###############################################################
#  Generated by:      Cadence Innovus 21.18-s099_1
#  OS:                Linux x86_64(Host ID ncdc-0137)
#  Generated on:      Wed Aug 12 09:11:18 2026
#  Design:            riscv_core
#  Command:           write_lef_abstract /home/cc/Documents/Abdullah/RISCV_synthesis/export/Innovus_Data/outputs/pnr/riscv_core_macro.lef -stripe_pins
###############################################################

VERSION 5.8 ;

BUSBITCHARS "[]" ;
DIVIDERCHAR "/" ;

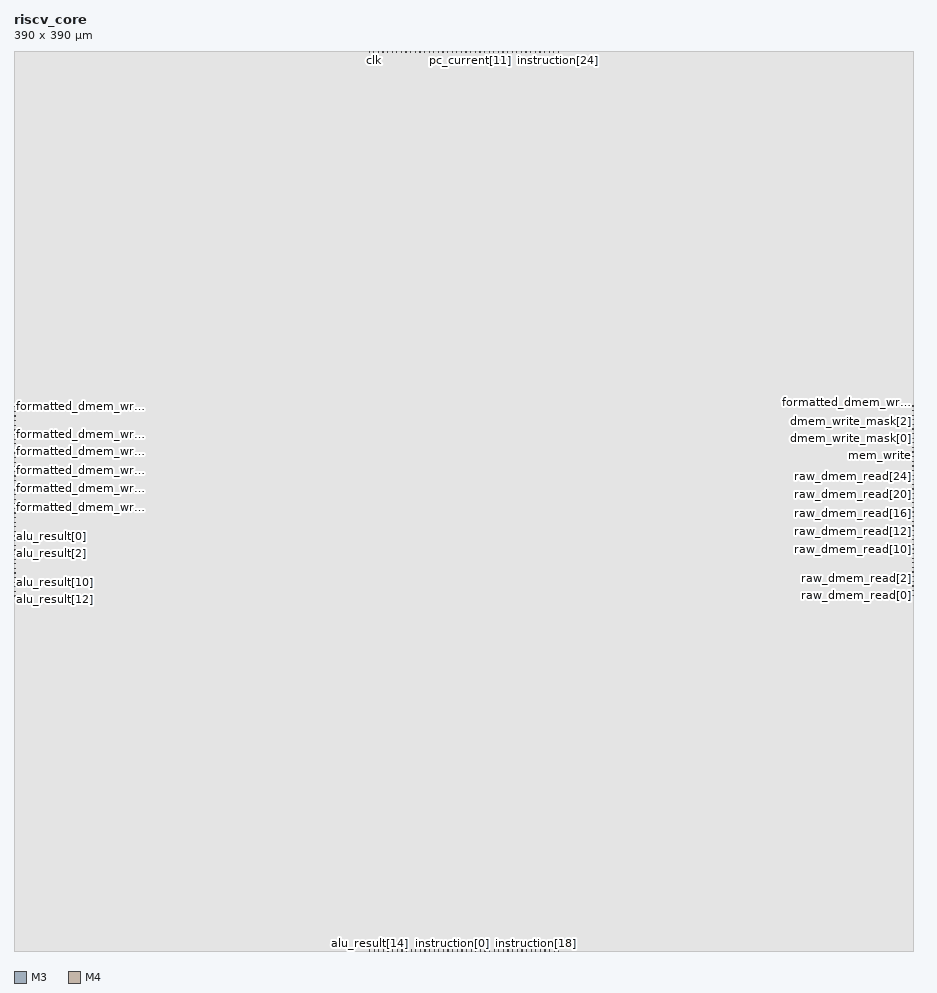
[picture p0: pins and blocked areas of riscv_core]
MACRO riscv_core
  CLASS BLOCK ;
  SIZE 390.000000 BY 390.000000 ;
  FOREIGN riscv_core -195.000000 -195.000000 ;
  ORIGIN 0 0 ;
  SYMMETRY X Y R90 ;
  PIN rst
    DIRECTION INPUT ;
    USE SIGNAL ;
    PORT
      LAYER M3 ;
        RECT 153.850000 389.480000 153.950000 390.000000 ;
    END
  END rst
  PIN clk
    DIRECTION INPUT ;
    USE SIGNAL ;
    PORT
      LAYER M3 ;
        RECT 155.850000 389.480000 155.950000 390.000000 ;
    END
  END clk
  PIN pc_current[31]
    DIRECTION OUTPUT ;
    USE SIGNAL ;
    PORT
      LAYER M3 ;
        RECT 157.850000 389.480000 157.950000 390.000000 ;
    END
  END pc_current[31]
  PIN pc_current[30]
    DIRECTION OUTPUT ;
    USE SIGNAL ;
    PORT
      LAYER M3 ;
        RECT 159.850000 389.480000 159.950000 390.000000 ;
    END
  END pc_current[30]
  PIN pc_current[29]
    DIRECTION OUTPUT ;
    USE SIGNAL ;
    PORT
      LAYER M3 ;
        RECT 161.850000 389.480000 161.950000 390.000000 ;
    END
  END pc_current[29]
  PIN pc_current[28]
    DIRECTION OUTPUT ;
    USE SIGNAL ;
    PORT
      LAYER M3 ;
        RECT 163.850000 389.480000 163.950000 390.000000 ;
    END
  END pc_current[28]
  PIN pc_current[27]
    DIRECTION OUTPUT ;
    USE SIGNAL ;
    PORT
      LAYER M3 ;
        RECT 165.850000 389.480000 165.950000 390.000000 ;
    END
  END pc_current[27]
  PIN pc_current[26]
    DIRECTION OUTPUT ;
    USE SIGNAL ;
    PORT
      LAYER M3 ;
        RECT 167.850000 389.480000 167.950000 390.000000 ;
    END
  END pc_current[26]
  PIN pc_current[25]
    DIRECTION OUTPUT ;
    USE SIGNAL ;
    PORT
      LAYER M3 ;
        RECT 169.850000 389.480000 169.950000 390.000000 ;
    END
  END pc_current[25]
  PIN pc_current[24]
    DIRECTION OUTPUT ;
    USE SIGNAL ;
    PORT
      LAYER M3 ;
        RECT 171.850000 389.480000 171.950000 390.000000 ;
    END
  END pc_current[24]
  PIN pc_current[23]
    DIRECTION OUTPUT ;
    USE SIGNAL ;
    PORT
      LAYER M3 ;
        RECT 173.850000 389.480000 173.950000 390.000000 ;
    END
  END pc_current[23]
  PIN pc_current[22]
    DIRECTION OUTPUT ;
    USE SIGNAL ;
    PORT
      LAYER M3 ;
        RECT 175.850000 389.480000 175.950000 390.000000 ;
    END
  END pc_current[22]
  PIN pc_current[21]
    DIRECTION OUTPUT ;
    USE SIGNAL ;
    PORT
      LAYER M3 ;
        RECT 177.850000 389.480000 177.950000 390.000000 ;
    END
  END pc_current[21]
  PIN pc_current[20]
    DIRECTION OUTPUT ;
    USE SIGNAL ;
    PORT
      LAYER M3 ;
        RECT 179.850000 389.480000 179.950000 390.000000 ;
    END
  END pc_current[20]
  PIN pc_current[19]
    DIRECTION OUTPUT ;
    USE SIGNAL ;
    PORT
      LAYER M3 ;
        RECT 181.850000 389.480000 181.950000 390.000000 ;
    END
  END pc_current[19]
  PIN pc_current[18]
    DIRECTION OUTPUT ;
    USE SIGNAL ;
    PORT
      LAYER M3 ;
        RECT 183.850000 389.480000 183.950000 390.000000 ;
    END
  END pc_current[18]
  PIN pc_current[17]
    DIRECTION OUTPUT ;
    USE SIGNAL ;
    PORT
      LAYER M3 ;
        RECT 185.850000 389.480000 185.950000 390.000000 ;
    END
  END pc_current[17]
  PIN pc_current[16]
    DIRECTION OUTPUT ;
    USE SIGNAL ;
    PORT
      LAYER M3 ;
        RECT 187.850000 389.480000 187.950000 390.000000 ;
    END
  END pc_current[16]
  PIN pc_current[15]
    DIRECTION OUTPUT ;
    USE SIGNAL ;
    PORT
      LAYER M3 ;
        RECT 189.850000 389.480000 189.950000 390.000000 ;
    END
  END pc_current[15]
  PIN pc_current[14]
    DIRECTION OUTPUT ;
    USE SIGNAL ;
    PORT
      LAYER M3 ;
        RECT 191.850000 389.480000 191.950000 390.000000 ;
    END
  END pc_current[14]
  PIN pc_current[13]
    DIRECTION OUTPUT ;
    USE SIGNAL ;
    PORT
      LAYER M3 ;
        RECT 193.850000 389.480000 193.950000 390.000000 ;
    END
  END pc_current[13]
  PIN pc_current[12]
    DIRECTION OUTPUT ;
    USE SIGNAL ;
    PORT
      LAYER M3 ;
        RECT 195.850000 389.480000 195.950000 390.000000 ;
    END
  END pc_current[12]
  PIN pc_current[11]
    DIRECTION OUTPUT ;
    USE SIGNAL ;
    PORT
      LAYER M3 ;
        RECT 197.850000 389.480000 197.950000 390.000000 ;
    END
  END pc_current[11]
  PIN pc_current[10]
    DIRECTION OUTPUT ;
    USE SIGNAL ;
    PORT
      LAYER M3 ;
        RECT 199.850000 389.480000 199.950000 390.000000 ;
    END
  END pc_current[10]
  PIN pc_current[9]
    DIRECTION OUTPUT ;
    USE SIGNAL ;
    PORT
      LAYER M3 ;
        RECT 201.850000 389.480000 201.950000 390.000000 ;
    END
  END pc_current[9]
  PIN pc_current[8]
    DIRECTION OUTPUT ;
    USE SIGNAL ;
    PORT
      LAYER M3 ;
        RECT 203.850000 389.480000 203.950000 390.000000 ;
    END
  END pc_current[8]
  PIN pc_current[7]
    DIRECTION OUTPUT ;
    USE SIGNAL ;
    PORT
      LAYER M3 ;
        RECT 205.850000 389.480000 205.950000 390.000000 ;
    END
  END pc_current[7]
  PIN pc_current[6]
    DIRECTION OUTPUT ;
    USE SIGNAL ;
    PORT
      LAYER M3 ;
        RECT 207.850000 389.480000 207.950000 390.000000 ;
    END
  END pc_current[6]
  PIN pc_current[5]
    DIRECTION OUTPUT ;
    USE SIGNAL ;
    PORT
      LAYER M3 ;
        RECT 209.850000 389.480000 209.950000 390.000000 ;
    END
  END pc_current[5]
  PIN pc_current[4]
    DIRECTION OUTPUT ;
    USE SIGNAL ;
    PORT
      LAYER M3 ;
        RECT 211.850000 389.480000 211.950000 390.000000 ;
    END
  END pc_current[4]
  PIN pc_current[3]
    DIRECTION OUTPUT ;
    USE SIGNAL ;
    PORT
      LAYER M3 ;
        RECT 213.850000 389.480000 213.950000 390.000000 ;
    END
  END pc_current[3]
  PIN pc_current[2]
    DIRECTION OUTPUT ;
    USE SIGNAL ;
    PORT
      LAYER M3 ;
        RECT 215.850000 389.480000 215.950000 390.000000 ;
    END
  END pc_current[2]
  PIN pc_current[1]
    DIRECTION OUTPUT ;
    USE SIGNAL ;
    PORT
      LAYER M3 ;
        RECT 217.850000 389.480000 217.950000 390.000000 ;
    END
  END pc_current[1]
  PIN pc_current[0]
    DIRECTION OUTPUT ;
    USE SIGNAL ;
    PORT
      LAYER M3 ;
        RECT 219.850000 389.480000 219.950000 390.000000 ;
    END
  END pc_current[0]
  PIN instruction[31]
    DIRECTION INPUT ;
    USE SIGNAL ;
    PORT
      LAYER M3 ;
        RECT 221.850000 389.480000 221.950000 390.000000 ;
    END
  END instruction[31]
  PIN instruction[30]
    DIRECTION INPUT ;
    USE SIGNAL ;
    PORT
      LAYER M3 ;
        RECT 223.850000 389.480000 223.950000 390.000000 ;
    END
  END instruction[30]
  PIN instruction[29]
    DIRECTION INPUT ;
    USE SIGNAL ;
    PORT
      LAYER M3 ;
        RECT 225.850000 389.480000 225.950000 390.000000 ;
    END
  END instruction[29]
  PIN instruction[28]
    DIRECTION INPUT ;
    USE SIGNAL ;
    PORT
      LAYER M3 ;
        RECT 227.850000 389.480000 227.950000 390.000000 ;
    END
  END instruction[28]
  PIN instruction[27]
    DIRECTION INPUT ;
    USE SIGNAL ;
    PORT
      LAYER M3 ;
        RECT 229.850000 389.480000 229.950000 390.000000 ;
    END
  END instruction[27]
  PIN instruction[26]
    DIRECTION INPUT ;
    USE SIGNAL ;
    PORT
      LAYER M3 ;
        RECT 231.850000 389.480000 231.950000 390.000000 ;
    END
  END instruction[26]
  PIN instruction[25]
    DIRECTION INPUT ;
    USE SIGNAL ;
    PORT
      LAYER M3 ;
        RECT 233.850000 389.480000 233.950000 390.000000 ;
    END
  END instruction[25]
  PIN instruction[24]
    DIRECTION INPUT ;
    USE SIGNAL ;
    PORT
      LAYER M3 ;
        RECT 235.850000 389.480000 235.950000 390.000000 ;
    END
  END instruction[24]
  PIN instruction[23]
    DIRECTION INPUT ;
    USE SIGNAL ;
    PORT
      LAYER M3 ;
        RECT 236.050000 0.000000 236.150000 0.520000 ;
    END
  END instruction[23]
  PIN instruction[22]
    DIRECTION INPUT ;
    USE SIGNAL ;
    PORT
      LAYER M3 ;
        RECT 234.050000 0.000000 234.150000 0.520000 ;
    END
  END instruction[22]
  PIN instruction[21]
    DIRECTION INPUT ;
    USE SIGNAL ;
    PORT
      LAYER M3 ;
        RECT 232.050000 0.000000 232.150000 0.520000 ;
    END
  END instruction[21]
  PIN instruction[20]
    DIRECTION INPUT ;
    USE SIGNAL ;
    PORT
      LAYER M3 ;
        RECT 230.050000 0.000000 230.150000 0.520000 ;
    END
  END instruction[20]
  PIN instruction[19]
    DIRECTION INPUT ;
    USE SIGNAL ;
    PORT
      LAYER M3 ;
        RECT 228.050000 0.000000 228.150000 0.520000 ;
    END
  END instruction[19]
  PIN instruction[18]
    DIRECTION INPUT ;
    USE SIGNAL ;
    PORT
      LAYER M3 ;
        RECT 226.050000 0.000000 226.150000 0.520000 ;
    END
  END instruction[18]
  PIN instruction[17]
    DIRECTION INPUT ;
    USE SIGNAL ;
    PORT
      LAYER M3 ;
        RECT 224.050000 0.000000 224.150000 0.520000 ;
    END
  END instruction[17]
  PIN instruction[16]
    DIRECTION INPUT ;
    USE SIGNAL ;
    PORT
      LAYER M3 ;
        RECT 222.050000 0.000000 222.150000 0.520000 ;
    END
  END instruction[16]
  PIN instruction[15]
    DIRECTION INPUT ;
    USE SIGNAL ;
    PORT
      LAYER M3 ;
        RECT 220.050000 0.000000 220.150000 0.520000 ;
    END
  END instruction[15]
  PIN instruction[14]
    DIRECTION INPUT ;
    USE SIGNAL ;
    PORT
      LAYER M3 ;
        RECT 218.050000 0.000000 218.150000 0.520000 ;
    END
  END instruction[14]
  PIN instruction[13]
    DIRECTION INPUT ;
    USE SIGNAL ;
    PORT
      LAYER M3 ;
        RECT 216.050000 0.000000 216.150000 0.520000 ;
    END
  END instruction[13]
  PIN instruction[12]
    DIRECTION INPUT ;
    USE SIGNAL ;
    PORT
      LAYER M3 ;
        RECT 214.050000 0.000000 214.150000 0.520000 ;
    END
  END instruction[12]
  PIN instruction[11]
    DIRECTION INPUT ;
    USE SIGNAL ;
    PORT
      LAYER M3 ;
        RECT 212.050000 0.000000 212.150000 0.520000 ;
    END
  END instruction[11]
  PIN instruction[10]
    DIRECTION INPUT ;
    USE SIGNAL ;
    PORT
      LAYER M3 ;
        RECT 210.050000 0.000000 210.150000 0.520000 ;
    END
  END instruction[10]
  PIN instruction[9]
    DIRECTION INPUT ;
    USE SIGNAL ;
    PORT
      LAYER M3 ;
        RECT 208.050000 0.000000 208.150000 0.520000 ;
    END
  END instruction[9]
  PIN instruction[8]
    DIRECTION INPUT ;
    USE SIGNAL ;
    PORT
      LAYER M3 ;
        RECT 206.050000 0.000000 206.150000 0.520000 ;
    END
  END instruction[8]
  PIN instruction[7]
    DIRECTION INPUT ;
    USE SIGNAL ;
    PORT
      LAYER M3 ;
        RECT 204.050000 0.000000 204.150000 0.520000 ;
    END
  END instruction[7]
  PIN instruction[6]
    DIRECTION INPUT ;
    USE SIGNAL ;
    PORT
      LAYER M3 ;
        RECT 202.050000 0.000000 202.150000 0.520000 ;
    END
  END instruction[6]
  PIN instruction[5]
    DIRECTION INPUT ;
    USE SIGNAL ;
    PORT
      LAYER M3 ;
        RECT 200.050000 0.000000 200.150000 0.520000 ;
    END
  END instruction[5]
  PIN instruction[4]
    DIRECTION INPUT ;
    USE SIGNAL ;
    PORT
      LAYER M3 ;
        RECT 198.050000 0.000000 198.150000 0.520000 ;
    END
  END instruction[4]
  PIN instruction[3]
    DIRECTION INPUT ;
    USE SIGNAL ;
    PORT
      LAYER M3 ;
        RECT 196.050000 0.000000 196.150000 0.520000 ;
    END
  END instruction[3]
  PIN instruction[2]
    DIRECTION INPUT ;
    USE SIGNAL ;
    PORT
      LAYER M3 ;
        RECT 194.050000 0.000000 194.150000 0.520000 ;
    END
  END instruction[2]
  PIN instruction[1]
    DIRECTION INPUT ;
    USE SIGNAL ;
    PORT
      LAYER M3 ;
        RECT 192.050000 0.000000 192.150000 0.520000 ;
    END
  END instruction[1]
  PIN instruction[0]
    DIRECTION INPUT ;
    USE SIGNAL ;
    PORT
      LAYER M3 ;
        RECT 190.050000 0.000000 190.150000 0.520000 ;
    END
  END instruction[0]
  PIN alu_result[31]
    DIRECTION OUTPUT ;
    USE SIGNAL ;
    PORT
      LAYER M3 ;
        RECT 188.050000 0.000000 188.150000 0.520000 ;
    END
  END alu_result[31]
  PIN alu_result[30]
    DIRECTION OUTPUT ;
    USE SIGNAL ;
    PORT
      LAYER M3 ;
        RECT 186.050000 0.000000 186.150000 0.520000 ;
    END
  END alu_result[30]
  PIN alu_result[29]
    DIRECTION OUTPUT ;
    USE SIGNAL ;
    PORT
      LAYER M3 ;
        RECT 184.050000 0.000000 184.150000 0.520000 ;
    END
  END alu_result[29]
  PIN alu_result[28]
    DIRECTION OUTPUT ;
    USE SIGNAL ;
    PORT
      LAYER M3 ;
        RECT 182.050000 0.000000 182.150000 0.520000 ;
    END
  END alu_result[28]
  PIN alu_result[27]
    DIRECTION OUTPUT ;
    USE SIGNAL ;
    PORT
      LAYER M3 ;
        RECT 180.050000 0.000000 180.150000 0.520000 ;
    END
  END alu_result[27]
  PIN alu_result[26]
    DIRECTION OUTPUT ;
    USE SIGNAL ;
    PORT
      LAYER M3 ;
        RECT 178.050000 0.000000 178.150000 0.520000 ;
    END
  END alu_result[26]
  PIN alu_result[25]
    DIRECTION OUTPUT ;
    USE SIGNAL ;
    PORT
      LAYER M3 ;
        RECT 176.050000 0.000000 176.150000 0.520000 ;
    END
  END alu_result[25]
  PIN alu_result[24]
    DIRECTION OUTPUT ;
    USE SIGNAL ;
    PORT
      LAYER M3 ;
        RECT 174.050000 0.000000 174.150000 0.520000 ;
    END
  END alu_result[24]
  PIN alu_result[23]
    DIRECTION OUTPUT ;
    USE SIGNAL ;
    PORT
      LAYER M3 ;
        RECT 172.050000 0.000000 172.150000 0.520000 ;
    END
  END alu_result[23]
  PIN alu_result[22]
    DIRECTION OUTPUT ;
    USE SIGNAL ;
    PORT
      LAYER M3 ;
        RECT 170.050000 0.000000 170.150000 0.520000 ;
    END
  END alu_result[22]
  PIN alu_result[21]
    DIRECTION OUTPUT ;
    USE SIGNAL ;
    PORT
      LAYER M3 ;
        RECT 168.050000 0.000000 168.150000 0.520000 ;
    END
  END alu_result[21]
  PIN alu_result[20]
    DIRECTION OUTPUT ;
    USE SIGNAL ;
    PORT
      LAYER M3 ;
        RECT 166.050000 0.000000 166.150000 0.520000 ;
    END
  END alu_result[20]
  PIN alu_result[19]
    DIRECTION OUTPUT ;
    USE SIGNAL ;
    PORT
      LAYER M3 ;
        RECT 164.050000 0.000000 164.150000 0.520000 ;
    END
  END alu_result[19]
  PIN alu_result[18]
    DIRECTION OUTPUT ;
    USE SIGNAL ;
    PORT
      LAYER M3 ;
        RECT 162.050000 0.000000 162.150000 0.520000 ;
    END
  END alu_result[18]
  PIN alu_result[17]
    DIRECTION OUTPUT ;
    USE SIGNAL ;
    PORT
      LAYER M3 ;
        RECT 160.050000 0.000000 160.150000 0.520000 ;
    END
  END alu_result[17]
  PIN alu_result[16]
    DIRECTION OUTPUT ;
    USE SIGNAL ;
    PORT
      LAYER M3 ;
        RECT 158.050000 0.000000 158.150000 0.520000 ;
    END
  END alu_result[16]
  PIN alu_result[15]
    DIRECTION OUTPUT ;
    USE SIGNAL ;
    PORT
      LAYER M3 ;
        RECT 156.050000 0.000000 156.150000 0.520000 ;
    END
  END alu_result[15]
  PIN alu_result[14]
    DIRECTION OUTPUT ;
    USE SIGNAL ;
    PORT
      LAYER M3 ;
        RECT 154.050000 0.000000 154.150000 0.520000 ;
    END
  END alu_result[14]
  PIN alu_result[13]
    DIRECTION OUTPUT ;
    USE SIGNAL ;
    PORT
      LAYER M4 ;
        RECT 0.000000 153.750000 0.520000 153.850000 ;
    END
  END alu_result[13]
  PIN alu_result[12]
    DIRECTION OUTPUT ;
    USE SIGNAL ;
    PORT
      LAYER M4 ;
        RECT 0.000000 155.750000 0.520000 155.850000 ;
    END
  END alu_result[12]
  PIN alu_result[11]
    DIRECTION OUTPUT ;
    USE SIGNAL ;
    PORT
      LAYER M4 ;
        RECT 0.000000 157.750000 0.520000 157.850000 ;
    END
  END alu_result[11]
  PIN alu_result[10]
    DIRECTION OUTPUT ;
    USE SIGNAL ;
    PORT
      LAYER M4 ;
        RECT 0.000000 159.750000 0.520000 159.850000 ;
    END
  END alu_result[10]
  PIN alu_result[9]
    DIRECTION OUTPUT ;
    USE SIGNAL ;
    PORT
      LAYER M4 ;
        RECT 0.000000 161.750000 0.520000 161.850000 ;
    END
  END alu_result[9]
  PIN alu_result[8]
    DIRECTION OUTPUT ;
    USE SIGNAL ;
    PORT
      LAYER M4 ;
        RECT 0.000000 163.750000 0.520000 163.850000 ;
    END
  END alu_result[8]
  PIN alu_result[7]
    DIRECTION OUTPUT ;
    USE SIGNAL ;
    PORT
      LAYER M4 ;
        RECT 0.000000 165.750000 0.520000 165.850000 ;
    END
  END alu_result[7]
  PIN alu_result[6]
    DIRECTION OUTPUT ;
    USE SIGNAL ;
    PORT
      LAYER M4 ;
        RECT 0.000000 167.750000 0.520000 167.850000 ;
    END
  END alu_result[6]
  PIN alu_result[5]
    DIRECTION OUTPUT ;
    USE SIGNAL ;
    PORT
      LAYER M4 ;
        RECT 0.000000 169.750000 0.520000 169.850000 ;
    END
  END alu_result[5]
  PIN alu_result[4]
    DIRECTION OUTPUT ;
    USE SIGNAL ;
    PORT
      LAYER M4 ;
        RECT 0.000000 171.750000 0.520000 171.850000 ;
    END
  END alu_result[4]
  PIN alu_result[3]
    DIRECTION OUTPUT ;
    USE SIGNAL ;
    PORT
      LAYER M4 ;
        RECT 0.000000 173.750000 0.520000 173.850000 ;
    END
  END alu_result[3]
  PIN alu_result[2]
    DIRECTION OUTPUT ;
    USE SIGNAL ;
    PORT
      LAYER M4 ;
        RECT 0.000000 175.750000 0.520000 175.850000 ;
    END
  END alu_result[2]
  PIN alu_result[1]
    DIRECTION OUTPUT ;
    USE SIGNAL ;
    PORT
      LAYER M4 ;
        RECT 0.000000 177.750000 0.520000 177.850000 ;
    END
  END alu_result[1]
  PIN alu_result[0]
    DIRECTION OUTPUT ;
    USE SIGNAL ;
    PORT
      LAYER M4 ;
        RECT 0.000000 179.750000 0.520000 179.850000 ;
    END
  END alu_result[0]
  PIN formatted_dmem_write[31]
    DIRECTION OUTPUT ;
    USE SIGNAL ;
    PORT
      LAYER M4 ;
        RECT 0.000000 181.750000 0.520000 181.850000 ;
    END
  END formatted_dmem_write[31]
  PIN formatted_dmem_write[30]
    DIRECTION OUTPUT ;
    USE SIGNAL ;
    PORT
      LAYER M4 ;
        RECT 0.000000 183.750000 0.520000 183.850000 ;
    END
  END formatted_dmem_write[30]
  PIN formatted_dmem_write[29]
    DIRECTION OUTPUT ;
    USE SIGNAL ;
    PORT
      LAYER M4 ;
        RECT 0.000000 185.750000 0.520000 185.850000 ;
    END
  END formatted_dmem_write[29]
  PIN formatted_dmem_write[28]
    DIRECTION OUTPUT ;
    USE SIGNAL ;
    PORT
      LAYER M4 ;
        RECT 0.000000 187.750000 0.520000 187.850000 ;
    END
  END formatted_dmem_write[28]
  PIN formatted_dmem_write[27]
    DIRECTION OUTPUT ;
    USE SIGNAL ;
    PORT
      LAYER M4 ;
        RECT 0.000000 189.750000 0.520000 189.850000 ;
    END
  END formatted_dmem_write[27]
  PIN formatted_dmem_write[26]
    DIRECTION OUTPUT ;
    USE SIGNAL ;
    PORT
      LAYER M4 ;
        RECT 0.000000 191.750000 0.520000 191.850000 ;
    END
  END formatted_dmem_write[26]
  PIN formatted_dmem_write[25]
    DIRECTION OUTPUT ;
    USE SIGNAL ;
    PORT
      LAYER M4 ;
        RECT 0.000000 193.750000 0.520000 193.850000 ;
    END
  END formatted_dmem_write[25]
  PIN formatted_dmem_write[24]
    DIRECTION OUTPUT ;
    USE SIGNAL ;
    PORT
      LAYER M4 ;
        RECT 0.000000 195.750000 0.520000 195.850000 ;
    END
  END formatted_dmem_write[24]
  PIN formatted_dmem_write[23]
    DIRECTION OUTPUT ;
    USE SIGNAL ;
    PORT
      LAYER M4 ;
        RECT 0.000000 197.750000 0.520000 197.850000 ;
    END
  END formatted_dmem_write[23]
  PIN formatted_dmem_write[22]
    DIRECTION OUTPUT ;
    USE SIGNAL ;
    PORT
      LAYER M4 ;
        RECT 0.000000 199.750000 0.520000 199.850000 ;
    END
  END formatted_dmem_write[22]
  PIN formatted_dmem_write[21]
    DIRECTION OUTPUT ;
    USE SIGNAL ;
    PORT
      LAYER M4 ;
        RECT 0.000000 201.750000 0.520000 201.850000 ;
    END
  END formatted_dmem_write[21]
  PIN formatted_dmem_write[20]
    DIRECTION OUTPUT ;
    USE SIGNAL ;
    PORT
      LAYER M4 ;
        RECT 0.000000 203.750000 0.520000 203.850000 ;
    END
  END formatted_dmem_write[20]
  PIN formatted_dmem_write[19]
    DIRECTION OUTPUT ;
    USE SIGNAL ;
    PORT
      LAYER M4 ;
        RECT 0.000000 205.750000 0.520000 205.850000 ;
    END
  END formatted_dmem_write[19]
  PIN formatted_dmem_write[18]
    DIRECTION OUTPUT ;
    USE SIGNAL ;
    PORT
      LAYER M4 ;
        RECT 0.000000 207.750000 0.520000 207.850000 ;
    END
  END formatted_dmem_write[18]
  PIN formatted_dmem_write[17]
    DIRECTION OUTPUT ;
    USE SIGNAL ;
    PORT
      LAYER M4 ;
        RECT 0.000000 209.750000 0.520000 209.850000 ;
    END
  END formatted_dmem_write[17]
  PIN formatted_dmem_write[16]
    DIRECTION OUTPUT ;
    USE SIGNAL ;
    PORT
      LAYER M4 ;
        RECT 0.000000 211.750000 0.520000 211.850000 ;
    END
  END formatted_dmem_write[16]
  PIN formatted_dmem_write[15]
    DIRECTION OUTPUT ;
    USE SIGNAL ;
    PORT
      LAYER M4 ;
        RECT 0.000000 213.750000 0.520000 213.850000 ;
    END
  END formatted_dmem_write[15]
  PIN formatted_dmem_write[14]
    DIRECTION OUTPUT ;
    USE SIGNAL ;
    PORT
      LAYER M4 ;
        RECT 0.000000 215.750000 0.520000 215.850000 ;
    END
  END formatted_dmem_write[14]
  PIN formatted_dmem_write[13]
    DIRECTION OUTPUT ;
    USE SIGNAL ;
    PORT
      LAYER M4 ;
        RECT 0.000000 217.750000 0.520000 217.850000 ;
    END
  END formatted_dmem_write[13]
  PIN formatted_dmem_write[12]
    DIRECTION OUTPUT ;
    USE SIGNAL ;
    PORT
      LAYER M4 ;
        RECT 0.000000 219.750000 0.520000 219.850000 ;
    END
  END formatted_dmem_write[12]
  PIN formatted_dmem_write[11]
    DIRECTION OUTPUT ;
    USE SIGNAL ;
    PORT
      LAYER M4 ;
        RECT 0.000000 221.750000 0.520000 221.850000 ;
    END
  END formatted_dmem_write[11]
  PIN formatted_dmem_write[10]
    DIRECTION OUTPUT ;
    USE SIGNAL ;
    PORT
      LAYER M4 ;
        RECT 0.000000 223.750000 0.520000 223.850000 ;
    END
  END formatted_dmem_write[10]
  PIN formatted_dmem_write[9]
    DIRECTION OUTPUT ;
    USE SIGNAL ;
    PORT
      LAYER M4 ;
        RECT 0.000000 225.750000 0.520000 225.850000 ;
    END
  END formatted_dmem_write[9]
  PIN formatted_dmem_write[8]
    DIRECTION OUTPUT ;
    USE SIGNAL ;
    PORT
      LAYER M4 ;
        RECT 0.000000 227.750000 0.520000 227.850000 ;
    END
  END formatted_dmem_write[8]
  PIN formatted_dmem_write[7]
    DIRECTION OUTPUT ;
    USE SIGNAL ;
    PORT
      LAYER M4 ;
        RECT 0.000000 229.750000 0.520000 229.850000 ;
    END
  END formatted_dmem_write[7]
  PIN formatted_dmem_write[6]
    DIRECTION OUTPUT ;
    USE SIGNAL ;
    PORT
      LAYER M4 ;
        RECT 0.000000 231.750000 0.520000 231.850000 ;
    END
  END formatted_dmem_write[6]
  PIN formatted_dmem_write[5]
    DIRECTION OUTPUT ;
    USE SIGNAL ;
    PORT
      LAYER M4 ;
        RECT 0.000000 233.750000 0.520000 233.850000 ;
    END
  END formatted_dmem_write[5]
  PIN formatted_dmem_write[4]
    DIRECTION OUTPUT ;
    USE SIGNAL ;
    PORT
      LAYER M4 ;
        RECT 0.000000 235.750000 0.520000 235.850000 ;
    END
  END formatted_dmem_write[4]
  PIN formatted_dmem_write[3]
    DIRECTION OUTPUT ;
    USE SIGNAL ;
    PORT
      LAYER M4 ;
        RECT 389.480000 236.150000 390.000000 236.250000 ;
    END
  END formatted_dmem_write[3]
  PIN formatted_dmem_write[2]
    DIRECTION OUTPUT ;
    USE SIGNAL ;
    PORT
      LAYER M4 ;
        RECT 389.480000 234.150000 390.000000 234.250000 ;
    END
  END formatted_dmem_write[2]
  PIN formatted_dmem_write[1]
    DIRECTION OUTPUT ;
    USE SIGNAL ;
    PORT
      LAYER M4 ;
        RECT 389.480000 232.150000 390.000000 232.250000 ;
    END
  END formatted_dmem_write[1]
  PIN formatted_dmem_write[0]
    DIRECTION OUTPUT ;
    USE SIGNAL ;
    PORT
      LAYER M4 ;
        RECT 389.480000 230.150000 390.000000 230.250000 ;
    END
  END formatted_dmem_write[0]
  PIN dmem_write_mask[3]
    DIRECTION OUTPUT ;
    USE SIGNAL ;
    PORT
      LAYER M4 ;
        RECT 389.480000 228.150000 390.000000 228.250000 ;
    END
  END dmem_write_mask[3]
  PIN dmem_write_mask[2]
    DIRECTION OUTPUT ;
    USE SIGNAL ;
    PORT
      LAYER M4 ;
        RECT 389.480000 226.150000 390.000000 226.250000 ;
    END
  END dmem_write_mask[2]
  PIN dmem_write_mask[1]
    DIRECTION OUTPUT ;
    USE SIGNAL ;
    PORT
      LAYER M4 ;
        RECT 389.480000 224.150000 390.000000 224.250000 ;
    END
  END dmem_write_mask[1]
  PIN dmem_write_mask[0]
    DIRECTION OUTPUT ;
    USE SIGNAL ;
    PORT
      LAYER M4 ;
        RECT 389.480000 222.150000 390.000000 222.250000 ;
    END
  END dmem_write_mask[0]
  PIN mem_read
    DIRECTION OUTPUT ;
    USE SIGNAL ;
    PORT
      LAYER M4 ;
        RECT 389.480000 220.150000 390.000000 220.250000 ;
    END
  END mem_read
  PIN mem_write
    DIRECTION OUTPUT ;
    USE SIGNAL ;
    PORT
      LAYER M4 ;
        RECT 389.480000 218.150000 390.000000 218.250000 ;
    END
  END mem_write
  PIN raw_dmem_read[31]
    DIRECTION INPUT ;
    USE SIGNAL ;
    PORT
      LAYER M4 ;
        RECT 389.480000 216.150000 390.000000 216.250000 ;
    END
  END raw_dmem_read[31]
  PIN raw_dmem_read[30]
    DIRECTION INPUT ;
    USE SIGNAL ;
    PORT
      LAYER M4 ;
        RECT 389.480000 214.150000 390.000000 214.250000 ;
    END
  END raw_dmem_read[30]
  PIN raw_dmem_read[29]
    DIRECTION INPUT ;
    USE SIGNAL ;
    PORT
      LAYER M4 ;
        RECT 389.480000 212.150000 390.000000 212.250000 ;
    END
  END raw_dmem_read[29]
  PIN raw_dmem_read[28]
    DIRECTION INPUT ;
    USE SIGNAL ;
    PORT
      LAYER M4 ;
        RECT 389.480000 210.150000 390.000000 210.250000 ;
    END
  END raw_dmem_read[28]
  PIN raw_dmem_read[27]
    DIRECTION INPUT ;
    USE SIGNAL ;
    PORT
      LAYER M4 ;
        RECT 389.480000 208.150000 390.000000 208.250000 ;
    END
  END raw_dmem_read[27]
  PIN raw_dmem_read[26]
    DIRECTION INPUT ;
    USE SIGNAL ;
    PORT
      LAYER M4 ;
        RECT 389.480000 206.150000 390.000000 206.250000 ;
    END
  END raw_dmem_read[26]
  PIN raw_dmem_read[25]
    DIRECTION INPUT ;
    USE SIGNAL ;
    PORT
      LAYER M4 ;
        RECT 389.480000 204.150000 390.000000 204.250000 ;
    END
  END raw_dmem_read[25]
  PIN raw_dmem_read[24]
    DIRECTION INPUT ;
    USE SIGNAL ;
    PORT
      LAYER M4 ;
        RECT 389.480000 202.150000 390.000000 202.250000 ;
    END
  END raw_dmem_read[24]
  PIN raw_dmem_read[23]
    DIRECTION INPUT ;
    USE SIGNAL ;
    PORT
      LAYER M4 ;
        RECT 389.480000 200.150000 390.000000 200.250000 ;
    END
  END raw_dmem_read[23]
  PIN raw_dmem_read[22]
    DIRECTION INPUT ;
    USE SIGNAL ;
    PORT
      LAYER M4 ;
        RECT 389.480000 198.150000 390.000000 198.250000 ;
    END
  END raw_dmem_read[22]
  PIN raw_dmem_read[21]
    DIRECTION INPUT ;
    USE SIGNAL ;
    PORT
      LAYER M4 ;
        RECT 389.480000 196.150000 390.000000 196.250000 ;
    END
  END raw_dmem_read[21]
  PIN raw_dmem_read[20]
    DIRECTION INPUT ;
    USE SIGNAL ;
    PORT
      LAYER M4 ;
        RECT 389.480000 194.150000 390.000000 194.250000 ;
    END
  END raw_dmem_read[20]
  PIN raw_dmem_read[19]
    DIRECTION INPUT ;
    USE SIGNAL ;
    PORT
      LAYER M4 ;
        RECT 389.480000 192.150000 390.000000 192.250000 ;
    END
  END raw_dmem_read[19]
  PIN raw_dmem_read[18]
    DIRECTION INPUT ;
    USE SIGNAL ;
    PORT
      LAYER M4 ;
        RECT 389.480000 190.150000 390.000000 190.250000 ;
    END
  END raw_dmem_read[18]
  PIN raw_dmem_read[17]
    DIRECTION INPUT ;
    USE SIGNAL ;
    PORT
      LAYER M4 ;
        RECT 389.480000 188.150000 390.000000 188.250000 ;
    END
  END raw_dmem_read[17]
  PIN raw_dmem_read[16]
    DIRECTION INPUT ;
    USE SIGNAL ;
    PORT
      LAYER M4 ;
        RECT 389.480000 186.150000 390.000000 186.250000 ;
    END
  END raw_dmem_read[16]
  PIN raw_dmem_read[15]
    DIRECTION INPUT ;
    USE SIGNAL ;
    PORT
      LAYER M4 ;
        RECT 389.480000 184.150000 390.000000 184.250000 ;
    END
  END raw_dmem_read[15]
  PIN raw_dmem_read[14]
    DIRECTION INPUT ;
    USE SIGNAL ;
    PORT
      LAYER M4 ;
        RECT 389.480000 182.150000 390.000000 182.250000 ;
    END
  END raw_dmem_read[14]
  PIN raw_dmem_read[13]
    DIRECTION INPUT ;
    USE SIGNAL ;
    PORT
      LAYER M4 ;
        RECT 389.480000 180.150000 390.000000 180.250000 ;
    END
  END raw_dmem_read[13]
  PIN raw_dmem_read[12]
    DIRECTION INPUT ;
    USE SIGNAL ;
    PORT
      LAYER M4 ;
        RECT 389.480000 178.150000 390.000000 178.250000 ;
    END
  END raw_dmem_read[12]
  PIN raw_dmem_read[11]
    DIRECTION INPUT ;
    USE SIGNAL ;
    PORT
      LAYER M4 ;
        RECT 389.480000 176.150000 390.000000 176.250000 ;
    END
  END raw_dmem_read[11]
  PIN raw_dmem_read[10]
    DIRECTION INPUT ;
    USE SIGNAL ;
    PORT
      LAYER M4 ;
        RECT 389.480000 174.150000 390.000000 174.250000 ;
    END
  END raw_dmem_read[10]
  PIN raw_dmem_read[9]
    DIRECTION INPUT ;
    USE SIGNAL ;
    PORT
      LAYER M4 ;
        RECT 389.480000 172.150000 390.000000 172.250000 ;
    END
  END raw_dmem_read[9]
  PIN raw_dmem_read[8]
    DIRECTION INPUT ;
    USE SIGNAL ;
    PORT
      LAYER M4 ;
        RECT 389.480000 170.150000 390.000000 170.250000 ;
    END
  END raw_dmem_read[8]
  PIN raw_dmem_read[7]
    DIRECTION INPUT ;
    USE SIGNAL ;
    PORT
      LAYER M4 ;
        RECT 389.480000 168.150000 390.000000 168.250000 ;
    END
  END raw_dmem_read[7]
  PIN raw_dmem_read[6]
    DIRECTION INPUT ;
    USE SIGNAL ;
    PORT
      LAYER M4 ;
        RECT 389.480000 166.150000 390.000000 166.250000 ;
    END
  END raw_dmem_read[6]
  PIN raw_dmem_read[5]
    DIRECTION INPUT ;
    USE SIGNAL ;
    PORT
      LAYER M4 ;
        RECT 389.480000 164.150000 390.000000 164.250000 ;
    END
  END raw_dmem_read[5]
  PIN raw_dmem_read[4]
    DIRECTION INPUT ;
    USE SIGNAL ;
    PORT
      LAYER M4 ;
        RECT 389.480000 162.150000 390.000000 162.250000 ;
    END
  END raw_dmem_read[4]
  PIN raw_dmem_read[3]
    DIRECTION INPUT ;
    USE SIGNAL ;
    PORT
      LAYER M4 ;
        RECT 389.480000 160.150000 390.000000 160.250000 ;
    END
  END raw_dmem_read[3]
  PIN raw_dmem_read[2]
    DIRECTION INPUT ;
    USE SIGNAL ;
    PORT
      LAYER M4 ;
        RECT 389.480000 158.150000 390.000000 158.250000 ;
    END
  END raw_dmem_read[2]
  PIN raw_dmem_read[1]
    DIRECTION INPUT ;
    USE SIGNAL ;
    PORT
      LAYER M4 ;
        RECT 389.480000 156.150000 390.000000 156.250000 ;
    END
  END raw_dmem_read[1]
  PIN raw_dmem_read[0]
    DIRECTION INPUT ;
    USE SIGNAL ;
    PORT
      LAYER M4 ;
        RECT 389.480000 154.150000 390.000000 154.250000 ;
    END
  END raw_dmem_read[0]
  OBS
    LAYER M1 ;
      RECT 0.000000 0.000000 390.000000 390.000000 ;
    LAYER M2 ;
      RECT 0.000000 0.000000 390.000000 390.000000 ;
    LAYER M3 ;
      RECT 236.110000 389.320000 390.000000 390.000000 ;
      RECT 234.110000 389.320000 235.690000 390.000000 ;
      RECT 232.110000 389.320000 233.690000 390.000000 ;
      RECT 230.110000 389.320000 231.690000 390.000000 ;
      RECT 228.110000 389.320000 229.690000 390.000000 ;
      RECT 226.110000 389.320000 227.690000 390.000000 ;
      RECT 224.110000 389.320000 225.690000 390.000000 ;
      RECT 222.110000 389.320000 223.690000 390.000000 ;
      RECT 220.110000 389.320000 221.690000 390.000000 ;
      RECT 218.110000 389.320000 219.690000 390.000000 ;
      RECT 216.110000 389.320000 217.690000 390.000000 ;
      RECT 214.110000 389.320000 215.690000 390.000000 ;
      RECT 212.110000 389.320000 213.690000 390.000000 ;
      RECT 210.110000 389.320000 211.690000 390.000000 ;
      RECT 208.110000 389.320000 209.690000 390.000000 ;
      RECT 206.110000 389.320000 207.690000 390.000000 ;
      RECT 204.110000 389.320000 205.690000 390.000000 ;
      RECT 202.110000 389.320000 203.690000 390.000000 ;
      RECT 200.110000 389.320000 201.690000 390.000000 ;
      RECT 198.110000 389.320000 199.690000 390.000000 ;
      RECT 196.110000 389.320000 197.690000 390.000000 ;
      RECT 194.110000 389.320000 195.690000 390.000000 ;
      RECT 192.110000 389.320000 193.690000 390.000000 ;
      RECT 190.110000 389.320000 191.690000 390.000000 ;
      RECT 188.110000 389.320000 189.690000 390.000000 ;
      RECT 186.110000 389.320000 187.690000 390.000000 ;
      RECT 184.110000 389.320000 185.690000 390.000000 ;
      RECT 182.110000 389.320000 183.690000 390.000000 ;
      RECT 180.110000 389.320000 181.690000 390.000000 ;
      RECT 178.110000 389.320000 179.690000 390.000000 ;
      RECT 176.110000 389.320000 177.690000 390.000000 ;
      RECT 174.110000 389.320000 175.690000 390.000000 ;
      RECT 172.110000 389.320000 173.690000 390.000000 ;
      RECT 170.110000 389.320000 171.690000 390.000000 ;
      RECT 168.110000 389.320000 169.690000 390.000000 ;
      RECT 166.110000 389.320000 167.690000 390.000000 ;
      RECT 164.110000 389.320000 165.690000 390.000000 ;
      RECT 162.110000 389.320000 163.690000 390.000000 ;
      RECT 160.110000 389.320000 161.690000 390.000000 ;
      RECT 158.110000 389.320000 159.690000 390.000000 ;
      RECT 156.110000 389.320000 157.690000 390.000000 ;
      RECT 154.110000 389.320000 155.690000 390.000000 ;
      RECT 0.000000 389.320000 153.690000 390.000000 ;
      RECT 0.000000 0.680000 390.000000 389.320000 ;
      RECT 236.310000 0.000000 390.000000 0.680000 ;
      RECT 234.310000 0.000000 235.890000 0.680000 ;
      RECT 232.310000 0.000000 233.890000 0.680000 ;
      RECT 230.310000 0.000000 231.890000 0.680000 ;
      RECT 228.310000 0.000000 229.890000 0.680000 ;
      RECT 226.310000 0.000000 227.890000 0.680000 ;
      RECT 224.310000 0.000000 225.890000 0.680000 ;
      RECT 222.310000 0.000000 223.890000 0.680000 ;
      RECT 220.310000 0.000000 221.890000 0.680000 ;
      RECT 218.310000 0.000000 219.890000 0.680000 ;
      RECT 216.310000 0.000000 217.890000 0.680000 ;
      RECT 214.310000 0.000000 215.890000 0.680000 ;
      RECT 212.310000 0.000000 213.890000 0.680000 ;
      RECT 210.310000 0.000000 211.890000 0.680000 ;
      RECT 208.310000 0.000000 209.890000 0.680000 ;
      RECT 206.310000 0.000000 207.890000 0.680000 ;
      RECT 204.310000 0.000000 205.890000 0.680000 ;
      RECT 202.310000 0.000000 203.890000 0.680000 ;
      RECT 200.310000 0.000000 201.890000 0.680000 ;
      RECT 198.310000 0.000000 199.890000 0.680000 ;
      RECT 196.310000 0.000000 197.890000 0.680000 ;
      RECT 194.310000 0.000000 195.890000 0.680000 ;
      RECT 192.310000 0.000000 193.890000 0.680000 ;
      RECT 190.310000 0.000000 191.890000 0.680000 ;
      RECT 188.310000 0.000000 189.890000 0.680000 ;
      RECT 186.310000 0.000000 187.890000 0.680000 ;
      RECT 184.310000 0.000000 185.890000 0.680000 ;
      RECT 182.310000 0.000000 183.890000 0.680000 ;
      RECT 180.310000 0.000000 181.890000 0.680000 ;
      RECT 178.310000 0.000000 179.890000 0.680000 ;
      RECT 176.310000 0.000000 177.890000 0.680000 ;
      RECT 174.310000 0.000000 175.890000 0.680000 ;
      RECT 172.310000 0.000000 173.890000 0.680000 ;
      RECT 170.310000 0.000000 171.890000 0.680000 ;
      RECT 168.310000 0.000000 169.890000 0.680000 ;
      RECT 166.310000 0.000000 167.890000 0.680000 ;
      RECT 164.310000 0.000000 165.890000 0.680000 ;
      RECT 162.310000 0.000000 163.890000 0.680000 ;
      RECT 160.310000 0.000000 161.890000 0.680000 ;
      RECT 158.310000 0.000000 159.890000 0.680000 ;
      RECT 156.310000 0.000000 157.890000 0.680000 ;
      RECT 154.310000 0.000000 155.890000 0.680000 ;
      RECT 0.000000 0.000000 153.890000 0.680000 ;
    LAYER M4 ;
      RECT 0.000000 236.410000 390.000000 390.000000 ;
      RECT 0.000000 236.010000 389.320000 236.410000 ;
      RECT 0.680000 235.990000 389.320000 236.010000 ;
      RECT 0.680000 235.590000 390.000000 235.990000 ;
      RECT 0.000000 234.410000 390.000000 235.590000 ;
      RECT 0.000000 234.010000 389.320000 234.410000 ;
      RECT 0.680000 233.990000 389.320000 234.010000 ;
      RECT 0.680000 233.590000 390.000000 233.990000 ;
      RECT 0.000000 232.410000 390.000000 233.590000 ;
      RECT 0.000000 232.010000 389.320000 232.410000 ;
      RECT 0.680000 231.990000 389.320000 232.010000 ;
      RECT 0.680000 231.590000 390.000000 231.990000 ;
      RECT 0.000000 230.410000 390.000000 231.590000 ;
      RECT 0.000000 230.010000 389.320000 230.410000 ;
      RECT 0.680000 229.990000 389.320000 230.010000 ;
      RECT 0.680000 229.590000 390.000000 229.990000 ;
      RECT 0.000000 228.410000 390.000000 229.590000 ;
      RECT 0.000000 228.010000 389.320000 228.410000 ;
      RECT 0.680000 227.990000 389.320000 228.010000 ;
      RECT 0.680000 227.590000 390.000000 227.990000 ;
      RECT 0.000000 226.410000 390.000000 227.590000 ;
      RECT 0.000000 226.010000 389.320000 226.410000 ;
      RECT 0.680000 225.990000 389.320000 226.010000 ;
      RECT 0.680000 225.590000 390.000000 225.990000 ;
      RECT 0.000000 224.410000 390.000000 225.590000 ;
      RECT 0.000000 224.010000 389.320000 224.410000 ;
      RECT 0.680000 223.990000 389.320000 224.010000 ;
      RECT 0.680000 223.590000 390.000000 223.990000 ;
      RECT 0.000000 222.410000 390.000000 223.590000 ;
      RECT 0.000000 222.010000 389.320000 222.410000 ;
      RECT 0.680000 221.990000 389.320000 222.010000 ;
      RECT 0.680000 221.590000 390.000000 221.990000 ;
      RECT 0.000000 220.410000 390.000000 221.590000 ;
      RECT 0.000000 220.010000 389.320000 220.410000 ;
      RECT 0.680000 219.990000 389.320000 220.010000 ;
      RECT 0.680000 219.590000 390.000000 219.990000 ;
      RECT 0.000000 218.410000 390.000000 219.590000 ;
      RECT 0.000000 218.010000 389.320000 218.410000 ;
      RECT 0.680000 217.990000 389.320000 218.010000 ;
      RECT 0.680000 217.590000 390.000000 217.990000 ;
      RECT 0.000000 216.410000 390.000000 217.590000 ;
      RECT 0.000000 216.010000 389.320000 216.410000 ;
      RECT 0.680000 215.990000 389.320000 216.010000 ;
      RECT 0.680000 215.590000 390.000000 215.990000 ;
      RECT 0.000000 214.410000 390.000000 215.590000 ;
      RECT 0.000000 214.010000 389.320000 214.410000 ;
      RECT 0.680000 213.990000 389.320000 214.010000 ;
      RECT 0.680000 213.590000 390.000000 213.990000 ;
      RECT 0.000000 212.410000 390.000000 213.590000 ;
      RECT 0.000000 212.010000 389.320000 212.410000 ;
      RECT 0.680000 211.990000 389.320000 212.010000 ;
      RECT 0.680000 211.590000 390.000000 211.990000 ;
      RECT 0.000000 210.410000 390.000000 211.590000 ;
      RECT 0.000000 210.010000 389.320000 210.410000 ;
      RECT 0.680000 209.990000 389.320000 210.010000 ;
      RECT 0.680000 209.590000 390.000000 209.990000 ;
      RECT 0.000000 208.410000 390.000000 209.590000 ;
      RECT 0.000000 208.010000 389.320000 208.410000 ;
      RECT 0.680000 207.990000 389.320000 208.010000 ;
      RECT 0.680000 207.590000 390.000000 207.990000 ;
      RECT 0.000000 206.410000 390.000000 207.590000 ;
      RECT 0.000000 206.010000 389.320000 206.410000 ;
      RECT 0.680000 205.990000 389.320000 206.010000 ;
      RECT 0.680000 205.590000 390.000000 205.990000 ;
      RECT 0.000000 204.410000 390.000000 205.590000 ;
      RECT 0.000000 204.010000 389.320000 204.410000 ;
      RECT 0.680000 203.990000 389.320000 204.010000 ;
      RECT 0.680000 203.590000 390.000000 203.990000 ;
      RECT 0.000000 202.410000 390.000000 203.590000 ;
      RECT 0.000000 202.010000 389.320000 202.410000 ;
      RECT 0.680000 201.990000 389.320000 202.010000 ;
      RECT 0.680000 201.590000 390.000000 201.990000 ;
      RECT 0.000000 200.410000 390.000000 201.590000 ;
      RECT 0.000000 200.010000 389.320000 200.410000 ;
      RECT 0.680000 199.990000 389.320000 200.010000 ;
      RECT 0.680000 199.590000 390.000000 199.990000 ;
      RECT 0.000000 198.410000 390.000000 199.590000 ;
      RECT 0.000000 198.010000 389.320000 198.410000 ;
      RECT 0.680000 197.990000 389.320000 198.010000 ;
      RECT 0.680000 197.590000 390.000000 197.990000 ;
      RECT 0.000000 196.410000 390.000000 197.590000 ;
      RECT 0.000000 196.010000 389.320000 196.410000 ;
      RECT 0.680000 195.990000 389.320000 196.010000 ;
      RECT 0.680000 195.590000 390.000000 195.990000 ;
      RECT 0.000000 194.410000 390.000000 195.590000 ;
      RECT 0.000000 194.010000 389.320000 194.410000 ;
      RECT 0.680000 193.990000 389.320000 194.010000 ;
      RECT 0.680000 193.590000 390.000000 193.990000 ;
      RECT 0.000000 192.410000 390.000000 193.590000 ;
      RECT 0.000000 192.010000 389.320000 192.410000 ;
      RECT 0.680000 191.990000 389.320000 192.010000 ;
      RECT 0.680000 191.590000 390.000000 191.990000 ;
      RECT 0.000000 190.410000 390.000000 191.590000 ;
      RECT 0.000000 190.010000 389.320000 190.410000 ;
      RECT 0.680000 189.990000 389.320000 190.010000 ;
      RECT 0.680000 189.590000 390.000000 189.990000 ;
      RECT 0.000000 188.410000 390.000000 189.590000 ;
      RECT 0.000000 188.010000 389.320000 188.410000 ;
      RECT 0.680000 187.990000 389.320000 188.010000 ;
      RECT 0.680000 187.590000 390.000000 187.990000 ;
      RECT 0.000000 186.410000 390.000000 187.590000 ;
      RECT 0.000000 186.010000 389.320000 186.410000 ;
      RECT 0.680000 185.990000 389.320000 186.010000 ;
      RECT 0.680000 185.590000 390.000000 185.990000 ;
      RECT 0.000000 184.410000 390.000000 185.590000 ;
      RECT 0.000000 184.010000 389.320000 184.410000 ;
      RECT 0.680000 183.990000 389.320000 184.010000 ;
      RECT 0.680000 183.590000 390.000000 183.990000 ;
      RECT 0.000000 182.410000 390.000000 183.590000 ;
      RECT 0.000000 182.010000 389.320000 182.410000 ;
      RECT 0.680000 181.990000 389.320000 182.010000 ;
      RECT 0.680000 181.590000 390.000000 181.990000 ;
      RECT 0.000000 180.410000 390.000000 181.590000 ;
      RECT 0.000000 180.010000 389.320000 180.410000 ;
      RECT 0.680000 179.990000 389.320000 180.010000 ;
      RECT 0.680000 179.590000 390.000000 179.990000 ;
      RECT 0.000000 178.410000 390.000000 179.590000 ;
      RECT 0.000000 178.010000 389.320000 178.410000 ;
      RECT 0.680000 177.990000 389.320000 178.010000 ;
      RECT 0.680000 177.590000 390.000000 177.990000 ;
      RECT 0.000000 176.410000 390.000000 177.590000 ;
      RECT 0.000000 176.010000 389.320000 176.410000 ;
      RECT 0.680000 175.990000 389.320000 176.010000 ;
      RECT 0.680000 175.590000 390.000000 175.990000 ;
      RECT 0.000000 174.410000 390.000000 175.590000 ;
      RECT 0.000000 174.010000 389.320000 174.410000 ;
      RECT 0.680000 173.990000 389.320000 174.010000 ;
      RECT 0.680000 173.590000 390.000000 173.990000 ;
      RECT 0.000000 172.410000 390.000000 173.590000 ;
      RECT 0.000000 172.010000 389.320000 172.410000 ;
      RECT 0.680000 171.990000 389.320000 172.010000 ;
      RECT 0.680000 171.590000 390.000000 171.990000 ;
      RECT 0.000000 170.410000 390.000000 171.590000 ;
      RECT 0.000000 170.010000 389.320000 170.410000 ;
      RECT 0.680000 169.990000 389.320000 170.010000 ;
      RECT 0.680000 169.590000 390.000000 169.990000 ;
      RECT 0.000000 168.410000 390.000000 169.590000 ;
      RECT 0.000000 168.010000 389.320000 168.410000 ;
      RECT 0.680000 167.990000 389.320000 168.010000 ;
      RECT 0.680000 167.590000 390.000000 167.990000 ;
      RECT 0.000000 166.410000 390.000000 167.590000 ;
      RECT 0.000000 166.010000 389.320000 166.410000 ;
      RECT 0.680000 165.990000 389.320000 166.010000 ;
      RECT 0.680000 165.590000 390.000000 165.990000 ;
      RECT 0.000000 164.410000 390.000000 165.590000 ;
      RECT 0.000000 164.010000 389.320000 164.410000 ;
      RECT 0.680000 163.990000 389.320000 164.010000 ;
      RECT 0.680000 163.590000 390.000000 163.990000 ;
      RECT 0.000000 162.410000 390.000000 163.590000 ;
      RECT 0.000000 162.010000 389.320000 162.410000 ;
      RECT 0.680000 161.990000 389.320000 162.010000 ;
      RECT 0.680000 161.590000 390.000000 161.990000 ;
      RECT 0.000000 160.410000 390.000000 161.590000 ;
      RECT 0.000000 160.010000 389.320000 160.410000 ;
      RECT 0.680000 159.990000 389.320000 160.010000 ;
      RECT 0.680000 159.590000 390.000000 159.990000 ;
      RECT 0.000000 158.410000 390.000000 159.590000 ;
      RECT 0.000000 158.010000 389.320000 158.410000 ;
      RECT 0.680000 157.990000 389.320000 158.010000 ;
      RECT 0.680000 157.590000 390.000000 157.990000 ;
      RECT 0.000000 156.410000 390.000000 157.590000 ;
      RECT 0.000000 156.010000 389.320000 156.410000 ;
      RECT 0.680000 155.990000 389.320000 156.010000 ;
      RECT 0.680000 155.590000 390.000000 155.990000 ;
      RECT 0.000000 154.410000 390.000000 155.590000 ;
      RECT 0.000000 154.010000 389.320000 154.410000 ;
      RECT 0.680000 153.990000 389.320000 154.010000 ;
      RECT 0.680000 153.590000 390.000000 153.990000 ;
      RECT 0.000000 0.000000 390.000000 153.590000 ;
    LAYER M5 ;
      RECT 0.000000 0.000000 390.000000 390.000000 ;
    LAYER M6 ;
      RECT 0.000000 0.000000 390.000000 390.000000 ;
    LAYER M7 ;
      RECT 0.000000 0.000000 390.000000 390.000000 ;
    LAYER M8 ;
      RECT 0.000000 0.000000 390.000000 390.000000 ;
    LAYER M9 ;
      RECT 0.000000 0.000000 390.000000 390.000000 ;
    LAYER AP ;
      RECT 0.000000 0.000000 390.000000 390.000000 ;
  END
END riscv_core

END LIBRARY
